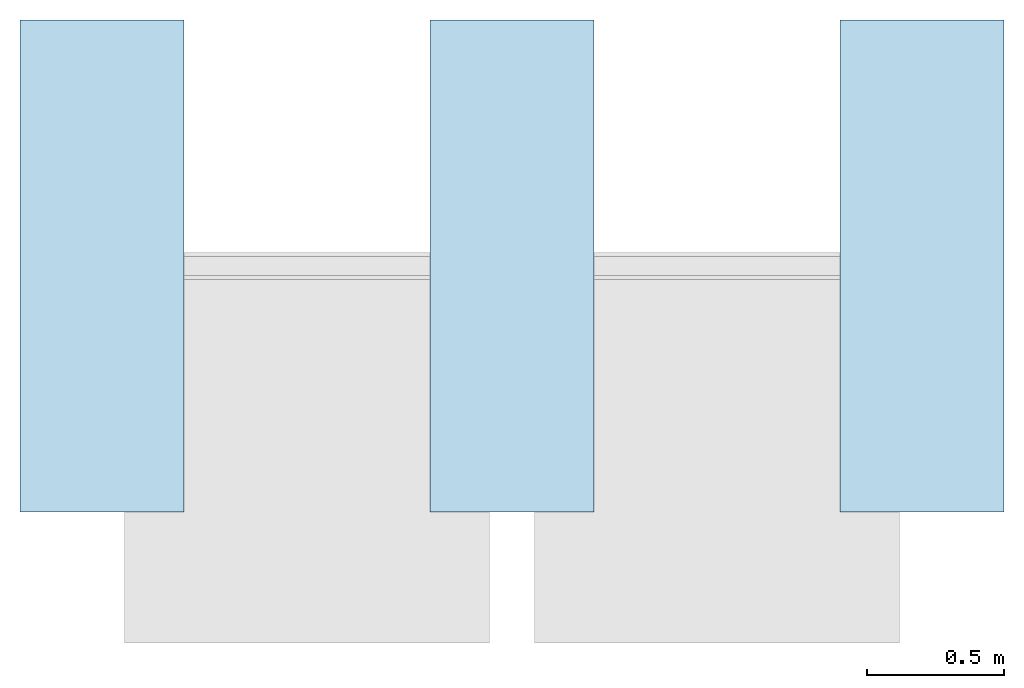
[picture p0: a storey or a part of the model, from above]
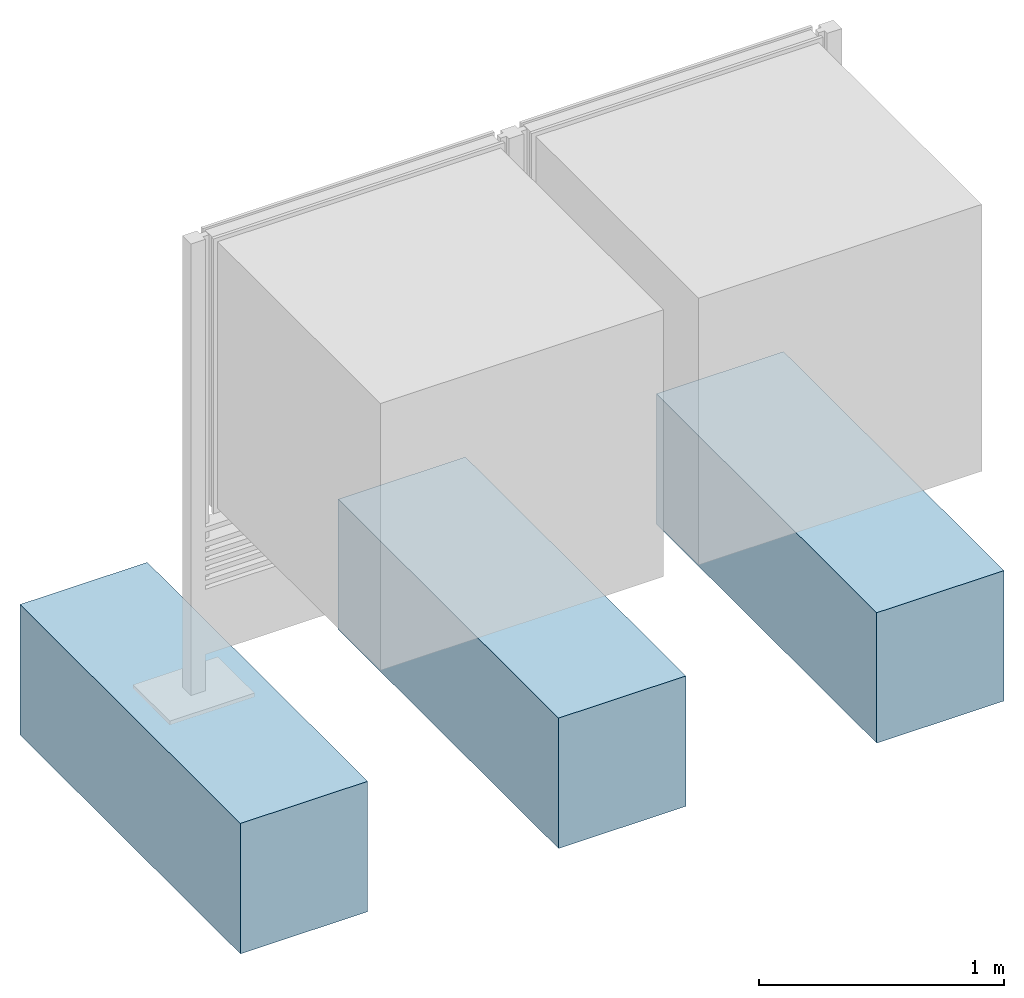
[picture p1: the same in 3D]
Properties of the parts of a building model (IFC4)

# File
Description: ViewDefinition [CoordinationView_V2.0], RevitIdentifiers [ContentGUID: d3ba7735-4996-4f2e-a220-48985317c84a, VersionGUID: 44f114b8-652d-4e34-88d7-4fcb713364eb, NumberOfSaves: 366]
File name: DB_Vitrine_Rahmenlos_DIN_A0_quadrat_zweifeldrig_einseitig.ifc
Time: 2026-05-19T18:07:26+01:00
Written by: ODA SDAI 24.6
Made in: Autodesk Revit 24.3.40.26 (DEU) - IFC 24.3.20.0

# IfcSite, Default
RefLatitude: 42, 24, 53, 508911; RefLongitude: -71, -15, -29, -58837; RefElevation: 0 m
Pset_SiteCommon - Reference: Projektinformationen

# IfcBuilding
Pset_BuildingCommon - Reference: Projektinformationen; NumberOfStoreys: 1
Pset_BuildingElementProxyCommon - Reference: Projektinformationen; IsExternal: no
Pset_BuildingStoreyCommon - Reference: Projektinformationen; sets with these values: 2

# IfcBuildingStorey: Ebene:Ebene, DB_Bezugshoehe_max_Bahnsteigkante
LongName: DB_Bezugshoehe_max_Bahnsteigkante; Elevation: 0 m
Pset_BuildingStoreyCommon - Reference: Ebene

# IfcBuildingStorey: Ebene:Hilfsebene PU, Ebene 0
LongName: Ebene 0; Elevation: 0 m
Pset_BuildingStoreyCommon - Reference: Hilfsebene PU

# IfcBuildingElementProxy: DB_Vitrine_Rahmenlos_DIN_A0_quadrat_zweifeldrig_einseitig:DB_Vitrine_Rahmenlos_DIN_A0_quadrat_zweifeldrig_einseitig, DB_Vitrine_Rahmenlos_DIN_A0_quadrat_zweifeldrig_einseitig:DB_Vitrine_Rahmenlos_DIN_A0_quadrat_zweifeldrig_einseitig:6432
In: DB_Bezugshoehe_max_Bahnsteigkante
Type - Material: DB_Aluminium_RAL9007, DB_Aluminium_RAL9006, DB_Stahl_verzinkt_RAL9006, DB_BedienUndRevisionsbereich, DB_weiss, DB_ESG/VSG_klar, DB_Kunststoff_RAL5022
Pset_BuildingElementProxyCommon - Reference: DB_Vitrine_Rahmenlos_DIN_A0_quadrat_zweifeldrig_einseitig; IsExternal: yes
Pset_EnvironmentalImpactIndicators - Reference: DB_Vitrine_Rahmenlos_DIN_A0_quadrat_zweifeldrig_einseitig
DB - AnzahlLeuchten: 0; DBAnlagentyp: Vitrinen; Objekt: DB Vitrine rahmenlos DIN A0 quadrat zweifeldrig einseitig; Objektklasse: Vitrine

# IfcSlab: DB_Vitrine_Fundament:DB_Vitrine_Fundament (3)
In: DB_Bezugshoehe_max_Bahnsteigkante
Type - PredefinedType: BASESLAB; Material: DB_Ortbeton
Pset_EnvironmentalImpactIndicators - Reference: DB_Vitrine_Fundament; sets with these values: 2
Pset_SlabCommon - Reference: DB_Vitrine_Fundament; IsExternal: no
DB - Objekt: DB Vitrine rahmenlos DIN A0 quadrat zweifeldrig einseitig; Objektklasse: Vitrine
Name (DB_Vitrine_Fundament:DB_Vitrine_Fundament:...)
4385132
4385133
4385134
